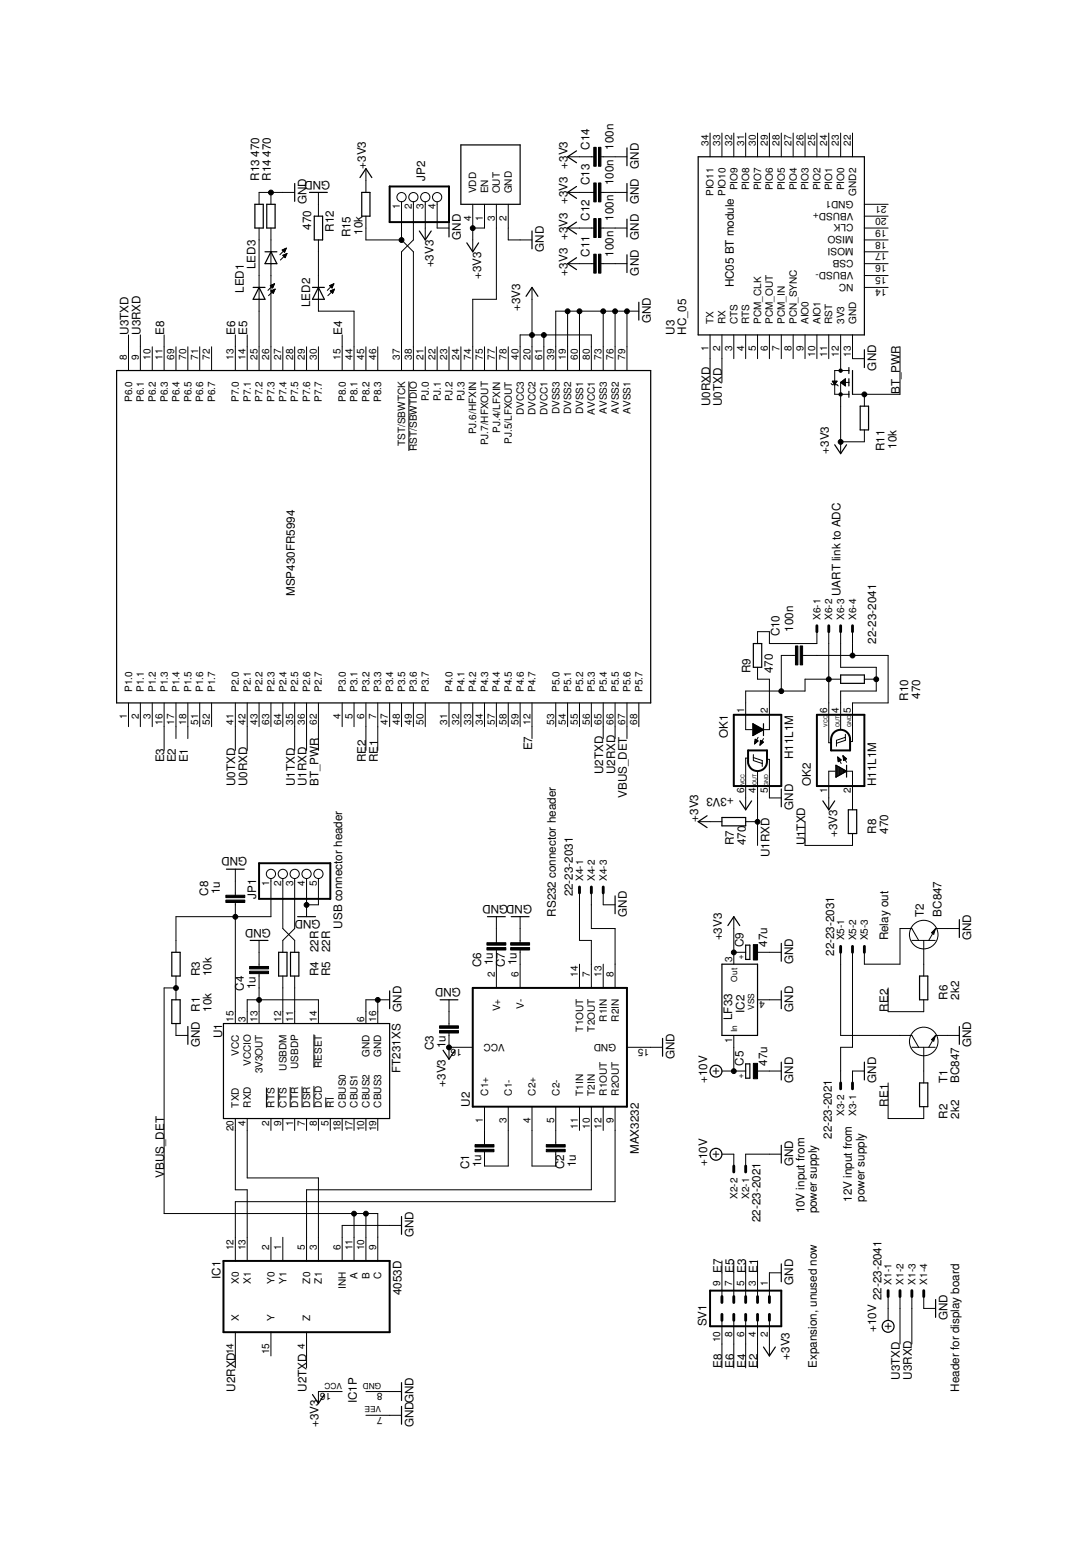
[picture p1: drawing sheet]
<svg xmlns="http://www.w3.org/2000/svg" width="210mm" height="297mm" viewBox="0 0 210 297" stroke-linecap="round" stroke-linejoin="round" font-family="sans-serif">
<defs><g id="words">
<g font-size="2.2">
<text x="109.3" y="29.9" transform="rotate(-90 109.3 29.9)">V3</text>
<text x="113.5" y="28.8" transform="rotate(-90 113.5 28.8)">C14</text>
<text x="118.1" y="28.8" transform="rotate(-90 118.1 28.8)">100n</text>
<text x="49.9" y="34.8" transform="rotate(-90 49.9 34.8)">R13</text>
<text x="49.9" y="30.2" transform="rotate(-90 49.9 30.2)">470</text>
<text x="52.2" y="34.8" transform="rotate(-90 52.2 34.8)">R14</text>
<text x="52.2" y="30.2" transform="rotate(-90 52.2 30.2)">470</text>
<text x="63.6" y="34.8" transform="rotate(-180 63.6 34.8)">GND</text>
<text x="70.5" y="32.5" transform="rotate(-90 70.5 32.5)">+3V3</text>
<text x="81.9" y="34.8" transform="rotate(-90 81.9 34.8)">JP2</text>
<text x="113.5" y="35.7" transform="rotate(-90 113.5 35.7)">C13</text>
<text x="118.1" y="35.7" transform="rotate(-90 118.1 35.7)">100n</text>
<text x="123" y="32.5" transform="rotate(-90 123 32.5)">GND</text>
<text x="59" y="39.3" transform="rotate(-90 59 39.3)">GND</text>
<text x="109.3" y="36.8" transform="rotate(-90 109.3 36.8)">V3 +3</text>
<text x="123" y="39.3" transform="rotate(-90 123 39.3)">GND</text>
<text x="60" y="44.2" transform="rotate(-90 60 44.2)">470</text>
<text x="64.3" y="44.6" transform="rotate(-90 64.3 44.6)">R12</text>
<text x="67.5" y="45.7" transform="rotate(-90 67.5 45.7)">R15</text>
<text x="69.8" y="45.2" transform="rotate(-90 69.8 45.2)">10k</text>
<text x="88.7" y="46.2" transform="rotate(-90 88.7 46.2)">GND</text>
<text x="109.3" y="43.6" transform="rotate(-90 109.3 43.6)">V3 +3</text>
<text x="113.5" y="42.5" transform="rotate(-90 113.5 42.5)">C12</text>
<text x="118.1" y="42.5" transform="rotate(-90 118.1 42.5)">100n</text>
<text x="123" y="46.2" transform="rotate(-90 123 46.2)">GND</text>
<text x="49.2" y="51.8" transform="rotate(-90 49.2 51.8)">LED3</text>
<text x="83.5" y="51.5" transform="rotate(-90 83.5 51.5)">+3V3</text>
<text x="92.6" y="53.8" transform="rotate(-90 92.6 53.8)">+3V3</text>
<text x="104.7" y="48.5" transform="rotate(-90 104.7 48.5)">GND</text>
<text x="109.3" y="53" transform="rotate(-90 109.3 53)">+3</text>
<text x="109.3" y="50.5" transform="rotate(-90 109.3 50.5)">V3 +3</text>
<text x="113.5" y="49.4" transform="rotate(-90 113.5 49.4)">C11</text>
<text x="118.1" y="49.4" transform="rotate(-90 118.1 49.4)">100n</text>
<text x="123" y="53" transform="rotate(-90 123 53)">GND</text>
<text x="46.9" y="56.4" transform="rotate(-90 46.9 56.4)">LED1</text>
<text x="59.7" y="59.1" transform="rotate(-90 59.7 59.1)">LED2</text>
<text x="100.2" y="59.9" transform="rotate(-90 100.2 59.9)">+3V3</text>
<text x="141.3" y="55.3" transform="rotate(-90 141.3 55.3)">HC05 BT module</text>
<text x="24.7" y="64.5" transform="rotate(-90 24.7 64.5)">U3TXD</text>
<text x="27" y="64.5" transform="rotate(-90 27 64.5)">U3RXD</text>
<text x="31.6" y="64.5" transform="rotate(-90 31.6 64.5)">E8</text>
<text x="45.3" y="64.5" transform="rotate(-90 45.3 64.5)">E6</text>
<text x="47.6" y="64.5" transform="rotate(-90 47.6 64.5)">E5</text>
<text x="65.9" y="64.5" transform="rotate(-90 65.9 64.5)">E4</text>
<text x="125.3" y="62.2" transform="rotate(-90 125.3 62.2)">GND</text>
<text x="129.9" y="64.5" transform="rotate(-90 129.9 64.5)">U3</text>
<text x="132.2" y="64.5" transform="rotate(-90 132.2 64.5)">HC_05</text>
<text x="168.7" y="71.3" transform="rotate(-90 168.7 71.3)">GND</text>
<text x="173.3" y="75.9" transform="rotate(-90 173.3 75.9)">BT_PWR</text>
<text x="136.7" y="78.2" transform="rotate(-90 136.7 78.2)">U0RXD</text>
<text x="139" y="78.2" transform="rotate(-90 139 78.2)">U0TXD</text>
<text x="159.6" y="87.3" transform="rotate(-90 159.6 87.3)">+3V3</text>
<text x="170.3" y="86.9" transform="rotate(-90 170.3 86.9)">R11</text>
<text x="172.6" y="86.4" transform="rotate(-90 172.6 86.4)">10k</text>
<text x="56.7" y="114.8" transform="rotate(-90 56.7 114.8)">MSP430FR5994</text>
<text x="161.9" y="114.8" transform="rotate(-90 161.9 114.8)">UART link to ADC</text>
<text x="150.1" y="122.5" transform="rotate(-90 150.1 122.5)">C10</text>
<text x="152.7" y="121.6" transform="rotate(-90 152.7 121.6)">100n</text>
<text x="168.7" y="123.9" transform="rotate(-90 168.7 123.9)">22-23-2041</text>
<text x="144.5" y="129.6" transform="rotate(-90 144.5 129.6)">R9</text>
<text x="148.9" y="129.6" transform="rotate(-90 148.9 129.6)">470</text>
<text x="174.9" y="134.9" transform="rotate(-90 174.9 134.9)">R10</text>
<text x="177.2" y="134.5" transform="rotate(-90 177.2 134.5)">470</text>
<text x="140.2" y="142.1" transform="rotate(-90 140.2 142.1)">OK1</text>
<text x="31.6" y="146.8" transform="rotate(-90 31.6 146.8)">E3</text>
<text x="33.9" y="146.8" transform="rotate(-90 33.9 146.8)">E2</text>
<text x="36.2" y="146.8" transform="rotate(-90 36.2 146.8)">E1</text>
<text x="70.5" y="146.8" transform="rotate(-90 70.5 146.8)">RE2</text>
<text x="72.7" y="146.8" transform="rotate(-90 72.7 146.8)">RE1</text>
<text x="102.5" y="144.5" transform="rotate(-90 102.5 144.5)">E7</text>
<text x="116.2" y="149" transform="rotate(-90 116.2 149)">U2TXD</text>
<text x="118.5" y="149" transform="rotate(-90 118.5 149)">U2RXD</text>
<text x="152.7" y="146.1" transform="rotate(-90 152.7 146.1)">H11L1M</text>
<text x="45.3" y="151.3" transform="rotate(-90 45.3 151.3)">U0TXD</text>
<text x="47.6" y="151.3" transform="rotate(-90 47.6 151.3)">U0RXD</text>
<text x="56.7" y="151.3" transform="rotate(-90 56.7 151.3)">U1TXD</text>
<text x="59" y="151.3" transform="rotate(-90 59 151.3)">U1RXD</text>
<text x="61.3" y="151.3" transform="rotate(-90 61.3 151.3)">BT_PWR</text>
<text x="120.7" y="153.6" transform="rotate(-90 120.7 153.6)">VBUS_DET</text>
<text x="141.3" y="153.6" transform="rotate(-180 141.3 153.6)">+3V3</text>
<text x="152.7" y="155.9" transform="rotate(-90 152.7 155.9)">GND</text>
<text x="156.2" y="151.3" transform="rotate(-90 156.2 151.3)">OK2</text>
<text x="168.7" y="151.3" transform="rotate(-90 168.7 151.3)">H11L1M</text>
<text x="134.5" y="158.2" transform="rotate(-90 134.5 158.2)">+3V3</text>
<text x="161.2" y="161.2" transform="rotate(-90 161.2 161.2)">+3V3</text>
<text x="168.7" y="160.5" transform="rotate(-90 168.7 160.5)">R8</text>
<text x="171" y="160.5" transform="rotate(-90 171 160.5)">470</text>
<text x="47.6" y="165" transform="rotate(-180 47.6 165)">GND</text>
<text x="141.3" y="162.8" transform="rotate(-90 141.3 162.8)">R7</text>
<text x="143.6" y="162.8" transform="rotate(-90 143.6 162.8)">470</text>
<text x="148.2" y="165" transform="rotate(-90 148.2 165)">U1RXD</text>
<text x="155" y="162.8" transform="rotate(-90 155 162.8)">U1TXD</text>
<text x="40.1" y="172.5" transform="rotate(-90 40.1 172.5)">C8</text>
<text x="42.4" y="172.1" transform="rotate(-90 42.4 172.1)">1u</text>
<text x="49.3" y="173" transform="rotate(-90 49.3 173)">JP1</text>
<text x="110.3" y="172.6" transform="rotate(-90 110.3 172.6)">22-23-2031</text>
<text x="52.2" y="178.8" transform="rotate(-180 52.2 178.8)">GND</text>
<text x="61.7" y="177.1" transform="rotate(-180 61.7 177.1)">GND</text>
<text x="65.9" y="178.8" transform="rotate(-90 65.9 178.8)">USB connector header</text>
<text x="102.5" y="174.2" transform="rotate(-180 102.5 174.2)">GNDGND</text>
<text x="107" y="176.5" transform="rotate(-90 107 176.5)">RS232 connector header</text>
<text x="120.7" y="176.5" transform="rotate(-90 120.7 176.5)">GND</text>
<text x="177.9" y="176.5" transform="rotate(-90 177.9 176.5)">T2</text>
<text x="181.3" y="176.5" transform="rotate(-90 181.3 176.5)">BC847</text>
<text x="61.3" y="183.3" transform="rotate(-90 61.3 183.3)">22R</text>
<text x="63.6" y="183.3" transform="rotate(-90 63.6 183.3)">22R</text>
<text x="94.9" y="185.8" transform="rotate(-90 94.9 185.8)">1u</text>
<text x="99.5" y="185.8" transform="rotate(-90 99.5 185.8)">1u</text>
<text x="139" y="181" transform="rotate(-90 139 181)">+3V3</text>
<text x="143.2" y="182.3" transform="rotate(-90 143.2 182.3)">C9</text>
<text x="147.7" y="182.3" transform="rotate(-90 147.7 182.3)">47u</text>
<text x="152.7" y="185.6" transform="rotate(-90 152.7 185.6)">GND</text>
<text x="160.6" y="184" transform="rotate(-90 160.6 184)">22-23-2031</text>
<text x="171" y="181" transform="rotate(-90 171 181)">Relay out</text>
<text x="187" y="181" transform="rotate(-90 187 181)">GND</text>
<text x="38.5" y="187.9" transform="rotate(-90 38.5 187.9)">R3</text>
<text x="40.7" y="187.9" transform="rotate(-90 40.7 187.9)">10k</text>
<text x="46.9" y="190.8" transform="rotate(-90 46.9 190.8)">C4</text>
<text x="49.2" y="190.4" transform="rotate(-90 49.2 190.4)">1u</text>
<text x="61.3" y="187.9" transform="rotate(-90 61.3 187.9)">R4</text>
<text x="63.6" y="187.9" transform="rotate(-90 63.6 187.9)">R5</text>
<text x="88.7" y="190.2" transform="rotate(-180 88.7 190.2)">GND</text>
<text x="92.6" y="186.2" transform="rotate(-90 92.6 186.2)">C6</text>
<text x="97.2" y="186.2" transform="rotate(-90 97.2 186.2)">C7</text>
<text x="38.5" y="194.8" transform="rotate(-90 38.5 194.8)">R1</text>
<text x="40.7" y="194.8" transform="rotate(-90 40.7 194.8)">10k</text>
<text x="77.3" y="194.8" transform="rotate(-90 77.3 194.8)">GND</text>
<text x="141" y="196.4" transform="rotate(-90 141 196.4)">LF33</text>
<text x="143.4" y="195" transform="rotate(-90 143.4 195)">IC2</text>
<text x="152.7" y="194.8" transform="rotate(-90 152.7 194.8)">GND</text>
<text x="171" y="194.8" transform="rotate(-90 171 194.8)">RE2</text>
<text x="182.4" y="192.5" transform="rotate(-90 182.4 192.5)">R6</text>
<text x="184.7" y="192.5" transform="rotate(-90 184.7 192.5)">2k2</text>
<text x="38.5" y="201.6" transform="rotate(-90 38.5 201.6)">GND</text>
<text x="42.8" y="199.9" transform="rotate(-90 42.8 199.9)">U1</text>
<text x="83.5" y="202.2" transform="rotate(-90 83.5 202.2)">C3</text>
<text x="85.8" y="201.8" transform="rotate(-90 85.8 201.8)">1u</text>
<text x="129.9" y="203.9" transform="rotate(-90 129.9 203.9)">GND</text>
<text x="187" y="201.6" transform="rotate(-90 187 201.6)">GND</text>
<text x="77.1" y="206.5" transform="rotate(-90 77.1 206.5)">FT231XS</text>
<text x="85.8" y="209.2" transform="rotate(-90 85.8 209.2)">+3V3</text>
<text x="136.2" y="208.5" transform="rotate(-90 136.2 208.5)">+10V</text>
<text x="143.2" y="205.2" transform="rotate(-90 143.2 205.2)">C5</text>
<text x="147.7" y="205.2" transform="rotate(-90 147.7 205.2)">47u</text>
<text x="152.7" y="208.5" transform="rotate(-90 152.7 208.5)">GND</text>
<text x="168.7" y="208.5" transform="rotate(-90 168.7 208.5)">GND</text>
<text x="182.4" y="208.5" transform="rotate(-90 182.4 208.5)">T1</text>
<text x="184.7" y="208.5" transform="rotate(-90 184.7 208.5)">BC847</text>
<text x="90.5" y="213" transform="rotate(-90 90.5 213)">U2</text>
<text x="171" y="213" transform="rotate(-90 171 213)">RE1</text>
<text x="182.4" y="215.3" transform="rotate(-90 182.4 215.3)">R2</text>
<text x="184.7" y="215.3" transform="rotate(-90 184.7 215.3)">2k2</text>
<text x="160.2" y="219.3" transform="rotate(-90 160.2 219.3)">22-23-2021</text>
<text x="31.6" y="226.8" transform="rotate(-90 31.6 226.8)">VBUS_DET</text>
<text x="90.4" y="225" transform="rotate(-90 90.4 225)">C1</text>
<text x="92.6" y="224.7" transform="rotate(-90 92.6 224.7)">1u</text>
<text x="108.6" y="225" transform="rotate(-90 108.6 225)">C2</text>
<text x="110.9" y="224.7" transform="rotate(-90 110.9 224.7)">1u</text>
<text x="123" y="222.2" transform="rotate(-90 123 222.2)">MAX3232</text>
<text x="136.2" y="224.5" transform="rotate(-90 136.2 224.5)">+10V</text>
<text x="152.7" y="224.5" transform="rotate(-90 152.7 224.5)">GND</text>
<text x="154.9" y="233.6" transform="rotate(-90 154.9 233.6)">10V input from</text>
<text x="157.3" y="233.6" transform="rotate(-90 157.3 233.6)">power supply</text>
<text x="164.1" y="231.3" transform="rotate(-90 164.1 231.3)">12V input from</text>
<text x="166.4" y="231.3" transform="rotate(-90 166.4 231.3)">power supply</text>
<text x="79.6" y="238.2" transform="rotate(-90 79.6 238.2)">GND</text>
<text x="146.5" y="235.3" transform="rotate(-90 146.5 235.3)">22-23-2021</text>
<text x="139" y="245" transform="rotate(-90 139 245)">E7</text>
<text x="141.3" y="245" transform="rotate(-90 141.3 245)">E5</text>
<text x="143.6" y="245" transform="rotate(-90 143.6 245)">E3</text>
<text x="145.9" y="245" transform="rotate(-90 145.9 245)">E1</text>
<text x="42.5" y="246.2" transform="rotate(-90 42.5 246.2)">IC1</text>
<text x="77.3" y="249.4" transform="rotate(-90 77.3 249.4)">4053D</text>
<text x="152.7" y="247.3" transform="rotate(-90 152.7 247.3)">GND</text>
<text x="169.8" y="250.3" transform="rotate(-90 169.8 250.3)">22-23-2041</text>
<text x="136.1" y="255.3" transform="rotate(-90 136.1 255.3)">SV1</text>
<text x="168.7" y="256.5" transform="rotate(-90 168.7 256.5)">+10V</text>
<text x="182.4" y="254.2" transform="rotate(-90 182.4 254.2)">GND</text>
<text x="139" y="263.3" transform="rotate(-90 139 263.3)">E8</text>
<text x="141.3" y="263.3" transform="rotate(-90 141.3 263.3)">E6</text>
<text x="143.6" y="263.3" transform="rotate(-90 143.6 263.3)">E4</text>
<text x="145.9" y="263.3" transform="rotate(-90 145.9 263.3)">E2</text>
<text x="152.1" y="261.8" transform="rotate(-90 152.1 261.8)">+3V3</text>
<text x="157.3" y="263.3" transform="rotate(-90 157.3 263.3)">Expansion, unused now</text>
<text x="45.3" y="267.9" transform="rotate(-90 45.3 267.9)">U2RXD</text>
<text x="59" y="267.9" transform="rotate(-90 59 267.9)">U2TXD</text>
<text x="173.3" y="265.6" transform="rotate(-90 173.3 265.6)">U3TXD</text>
<text x="175.6" y="265.6" transform="rotate(-90 175.6 265.6)">U3RXD</text>
<text x="184.7" y="267.9" transform="rotate(-90 184.7 267.9)">Header for display board</text>
<text x="61.3" y="274.7" transform="rotate(-90 61.3 274.7)">+3V3</text>
<text x="68.7" y="270.2" transform="rotate(-90 68.7 270.2)">IC1P</text>
<text x="79.6" y="274.7" transform="rotate(-90 79.6 274.7)">GNDGND</text>
</g>
<g font-size="1.9">
<text x="136.4" y="28.1" transform="rotate(-90 136.4 28.1)">34</text>
<text x="138.7" y="28.1" transform="rotate(-90 138.7 28.1)">33</text>
<text x="141" y="28.1" transform="rotate(-90 141 28.1)">32</text>
<text x="143.3" y="28.1" transform="rotate(-90 143.3 28.1)">31</text>
<text x="145.6" y="28.1" transform="rotate(-90 145.6 28.1)">30</text>
<text x="147.8" y="28.1" transform="rotate(-90 147.8 28.1)">29</text>
<text x="150.1" y="28.1" transform="rotate(-90 150.1 28.1)">28</text>
<text x="152.4" y="28.1" transform="rotate(-90 152.4 28.1)">27</text>
<text x="154.7" y="28.1" transform="rotate(-90 154.7 28.1)">26</text>
<text x="157" y="28.1" transform="rotate(-90 157 28.1)">25</text>
<text x="159.3" y="28.1" transform="rotate(-90 159.3 28.1)">24</text>
<text x="161.6" y="28.1" transform="rotate(-90 161.6 28.1)">23</text>
<text x="163.8" y="28.1" transform="rotate(-90 163.8 28.1)">22</text>
<text x="77" y="40.2" transform="rotate(-90 77 40.2)">1</text>
<text x="79.3" y="40.2" transform="rotate(-90 79.3 40.2)">2</text>
<text x="81.6" y="40.2" transform="rotate(-90 81.6 40.2)">3</text>
<text x="83.9" y="40.2" transform="rotate(-90 83.9 40.2)">4</text>
<text x="91.7" y="37.2" transform="rotate(-90 91.7 37.2)">VDD</text>
<text x="94" y="37.2" transform="rotate(-90 94 37.2)">EN</text>
<text x="96.3" y="37.2" transform="rotate(-90 96.3 37.2)">OUT</text>
<text x="98.6" y="37.2" transform="rotate(-90 98.6 37.2)">GND</text>
<text x="137.4" y="37.7" transform="rotate(-90 137.4 37.7)">PIO11</text>
<text x="139.7" y="37.7" transform="rotate(-90 139.7 37.7)">PIO10</text>
<text x="142" y="36.7" transform="rotate(-90 142 36.7)">PIO9</text>
<text x="144.3" y="36.7" transform="rotate(-90 144.3 36.7)">PIO8</text>
<text x="146.6" y="36.7" transform="rotate(-90 146.6 36.7)">PIO7</text>
<text x="148.9" y="36.7" transform="rotate(-90 148.9 36.7)">PIO6</text>
<text x="151.1" y="36.7" transform="rotate(-90 151.1 36.7)">PIO5</text>
<text x="153.4" y="36.7" transform="rotate(-90 153.4 36.7)">PIO4</text>
<text x="155.7" y="36.7" transform="rotate(-90 155.7 36.7)">PIO3</text>
<text x="158" y="36.7" transform="rotate(-90 158 36.7)">PIO2</text>
<text x="160.3" y="36.7" transform="rotate(-90 160.3 36.7)">PIO1</text>
<text x="162.6" y="36.7" transform="rotate(-90 162.6 36.7)">PIO0</text>
<text x="164.3" y="40.9" transform="rotate(-180 164.3 40.9)">VBUSD+</text>
<text x="164.3" y="38.6" transform="rotate(-180 164.3 38.6)">GND1</text>
<text x="164.9" y="37.6" transform="rotate(-90 164.9 37.6)">GND2</text>
<text x="170.7" y="41.9" transform="rotate(-180 170.7 41.9)">20</text>
<text x="170.7" y="39.6" transform="rotate(-180 170.7 39.6)">21</text>
<text x="90.7" y="42.5" transform="rotate(-90 90.7 42.5)">4</text>
<text x="93" y="42.5" transform="rotate(-90 93 42.5)">1</text>
<text x="95.3" y="42.5" transform="rotate(-90 95.3 42.5)">3</text>
<text x="97.6" y="42.5" transform="rotate(-90 97.6 42.5)">2</text>
<text x="164.3" y="47.8" transform="rotate(-180 164.3 47.8)">MOSI</text>
<text x="164.3" y="45.5" transform="rotate(-180 164.3 45.5)">MISO</text>
<text x="164.3" y="43.2" transform="rotate(-180 164.3 43.2)">CLK</text>
<text x="170.7" y="46.5" transform="rotate(-180 170.7 46.5)">18</text>
<text x="170.7" y="44.2" transform="rotate(-180 170.7 44.2)">19</text>
<text x="164.3" y="52.4" transform="rotate(-180 164.3 52.4)">VBUSD-</text>
<text x="164.3" y="50.1" transform="rotate(-180 164.3 50.1)">CSB</text>
<text x="170.7" y="53.4" transform="rotate(-180 170.7 53.4)">15</text>
<text x="170.7" y="51.1" transform="rotate(-180 170.7 51.1)">16</text>
<text x="170.7" y="48.8" transform="rotate(-180 170.7 48.8)">17</text>
<text x="164.3" y="54.6" transform="rotate(-180 164.3 54.6)">NC</text>
<text x="170.7" y="55.6" transform="rotate(-180 170.7 55.6)">14</text>
<text x="137.4" y="62.4" transform="rotate(-90 137.4 62.4)">TX</text>
<text x="139.7" y="62.4" transform="rotate(-90 139.7 62.4)">RX</text>
<text x="142" y="62.4" transform="rotate(-90 142 62.4)">CTS</text>
<text x="144.3" y="62.4" transform="rotate(-90 144.3 62.4)">RTS</text>
<text x="146.6" y="62.4" transform="rotate(-90 146.6 62.4)">PCM_CLK</text>
<text x="148.9" y="62.4" transform="rotate(-90 148.9 62.4)">PCM_OUT</text>
<text x="151.1" y="62.4" transform="rotate(-90 151.1 62.4)">PCM_IN</text>
<text x="153.4" y="62.4" transform="rotate(-90 153.4 62.4)">PCN_SYNC</text>
<text x="155.7" y="62.4" transform="rotate(-90 155.7 62.4)">AIO0</text>
<text x="158" y="62.4" transform="rotate(-90 158 62.4)">AIO1</text>
<text x="160.3" y="62.4" transform="rotate(-90 160.3 62.4)">RST</text>
<text x="162.6" y="62.4" transform="rotate(-90 162.6 62.4)">3V3</text>
<text x="164.9" y="62.4" transform="rotate(-90 164.9 62.4)">GND</text>
<text x="24.4" y="69.2" transform="rotate(-90 24.4 69.2)">8</text>
<text x="26.7" y="69.2" transform="rotate(-90 26.7 69.2)">9</text>
<text x="29" y="69.2" transform="rotate(-90 29 69.2)">10</text>
<text x="31.3" y="69.2" transform="rotate(-90 31.3 69.2)">11</text>
<text x="33.6" y="69.2" transform="rotate(-90 33.6 69.2)">69</text>
<text x="35.9" y="69.2" transform="rotate(-90 35.9 69.2)">70</text>
<text x="38.1" y="69.2" transform="rotate(-90 38.1 69.2)">71</text>
<text x="40.4" y="69.2" transform="rotate(-90 40.4 69.2)">72</text>
<text x="45" y="69.2" transform="rotate(-90 45 69.2)">13</text>
<text x="47.3" y="69.2" transform="rotate(-90 47.3 69.2)">14</text>
<text x="49.6" y="69.2" transform="rotate(-90 49.6 69.2)">25</text>
<text x="51.9" y="69.2" transform="rotate(-90 51.9 69.2)">26</text>
<text x="54.1" y="69.2" transform="rotate(-90 54.1 69.2)">27</text>
<text x="56.4" y="69.2" transform="rotate(-90 56.4 69.2)">28</text>
<text x="58.7" y="69.2" transform="rotate(-90 58.7 69.2)">29</text>
<text x="61" y="69.2" transform="rotate(-90 61 69.2)">30</text>
<text x="65.6" y="69.2" transform="rotate(-90 65.6 69.2)">15</text>
<text x="67.9" y="69.2" transform="rotate(-90 67.9 69.2)">44</text>
<text x="70.1" y="69.2" transform="rotate(-90 70.1 69.2)">45</text>
<text x="72.4" y="69.2" transform="rotate(-90 72.4 69.2)">46</text>
<text x="77" y="69.2" transform="rotate(-90 77 69.2)">37</text>
<text x="79.3" y="69.2" transform="rotate(-90 79.3 69.2)">38</text>
<text x="81.6" y="69.2" transform="rotate(-90 81.6 69.2)">21</text>
<text x="83.9" y="69.2" transform="rotate(-90 83.9 69.2)">22</text>
<text x="86.1" y="69.2" transform="rotate(-90 86.1 69.2)">23</text>
<text x="88.4" y="69.2" transform="rotate(-90 88.4 69.2)">24</text>
<text x="90.7" y="69.2" transform="rotate(-90 90.7 69.2)">74</text>
<text x="93" y="69.2" transform="rotate(-90 93 69.2)">75</text>
<text x="95.3" y="69.2" transform="rotate(-90 95.3 69.2)">77</text>
<text x="97.6" y="69.2" transform="rotate(-90 97.6 69.2)">78</text>
<text x="99.8" y="69.2" transform="rotate(-90 99.8 69.2)">40</text>
<text x="102.1" y="69.2" transform="rotate(-90 102.1 69.2)">20</text>
<text x="104.4" y="69.2" transform="rotate(-90 104.4 69.2)">61</text>
<text x="106.7" y="69.2" transform="rotate(-90 106.7 69.2)">39</text>
<text x="109" y="69.2" transform="rotate(-90 109 69.2)">19</text>
<text x="111.3" y="69.2" transform="rotate(-90 111.3 69.2)">60</text>
<text x="113.6" y="69.2" transform="rotate(-90 113.6 69.2)">80</text>
<text x="115.8" y="69.2" transform="rotate(-90 115.8 69.2)">73</text>
<text x="118.1" y="69.2" transform="rotate(-90 118.1 69.2)">76</text>
<text x="120.4" y="69.2" transform="rotate(-90 120.4 69.2)">79</text>
<text x="136.4" y="67.7" transform="rotate(-90 136.4 67.7)">1</text>
<text x="138.7" y="67.7" transform="rotate(-90 138.7 67.7)">2</text>
<text x="141" y="67.7" transform="rotate(-90 141 67.7)">3</text>
<text x="143.3" y="67.7" transform="rotate(-90 143.3 67.7)">4</text>
<text x="145.6" y="67.7" transform="rotate(-90 145.6 67.7)">5</text>
<text x="147.8" y="67.7" transform="rotate(-90 147.8 67.7)">6</text>
<text x="150.1" y="67.7" transform="rotate(-90 150.1 67.7)">7</text>
<text x="152.4" y="67.7" transform="rotate(-90 152.4 67.7)">8</text>
<text x="154.7" y="67.7" transform="rotate(-90 154.7 67.7)">9</text>
<text x="157" y="68.7" transform="rotate(-90 157 68.7)">10</text>
<text x="159.3" y="68.7" transform="rotate(-90 159.3 68.7)">11</text>
<text x="161.6" y="68.7" transform="rotate(-90 161.6 68.7)">12</text>
<text x="163.8" y="68.7" transform="rotate(-90 163.8 68.7)">13</text>
<text x="25.4" y="77.4" transform="rotate(-90 25.4 77.4)">P6.0</text>
<text x="27.7" y="77.4" transform="rotate(-90 27.7 77.4)">P6.1</text>
<text x="30" y="77.4" transform="rotate(-90 30 77.4)">P6.2</text>
<text x="32.3" y="77.4" transform="rotate(-90 32.3 77.4)">P6.3</text>
<text x="34.6" y="77.4" transform="rotate(-90 34.6 77.4)">P6.4</text>
<text x="36.9" y="77.4" transform="rotate(-90 36.9 77.4)">P6.5</text>
<text x="39.2" y="77.4" transform="rotate(-90 39.2 77.4)">P6.6</text>
<text x="41.4" y="77.4" transform="rotate(-90 41.4 77.4)">P6.7</text>
<text x="46" y="77.4" transform="rotate(-90 46 77.4)">P7.0</text>
<text x="48.3" y="77.4" transform="rotate(-90 48.3 77.4)">P7.1</text>
<text x="50.6" y="77.4" transform="rotate(-90 50.6 77.4)">P7.2</text>
<text x="52.9" y="77.4" transform="rotate(-90 52.9 77.4)">P7.3</text>
<text x="55.1" y="77.4" transform="rotate(-90 55.1 77.4)">P7.4</text>
<text x="57.4" y="77.4" transform="rotate(-90 57.4 77.4)">P7.5</text>
<text x="59.7" y="77.4" transform="rotate(-90 59.7 77.4)">P7.6</text>
<text x="62" y="77.4" transform="rotate(-90 62 77.4)">P7.7</text>
<text x="66.6" y="77.4" transform="rotate(-90 66.6 77.4)">P8.0</text>
<text x="68.9" y="77.4" transform="rotate(-90 68.9 77.4)">P8.1</text>
<text x="71.1" y="77.4" transform="rotate(-90 71.1 77.4)">P8.2</text>
<text x="73.4" y="77.4" transform="rotate(-90 73.4 77.4)">P8.3</text>
<text x="82.6" y="77.3" transform="rotate(-90 82.6 77.3)">PJ.0</text>
<text x="84.9" y="77.3" transform="rotate(-90 84.9 77.3)">PJ.1</text>
<text x="87.1" y="77.3" transform="rotate(-90 87.1 77.3)">PJ.2</text>
<text x="89.4" y="77.3" transform="rotate(-90 89.4 77.3)">PJ.3</text>
<text x="91.7" y="83.6" transform="rotate(-90 91.7 83.6)">PJ.6/HFXIN</text>
<text x="96.3" y="83.3" transform="rotate(-90 96.3 83.3)">PJ.4/LFXIN</text>
<text x="100.9" y="79.9" transform="rotate(-90 100.9 79.9)">DVCC3</text>
<text x="103.1" y="79.9" transform="rotate(-90 103.1 79.9)">DVCC2</text>
<text x="105.4" y="79.9" transform="rotate(-90 105.4 79.9)">DVCC1</text>
<text x="107.7" y="79.7" transform="rotate(-90 107.7 79.7)">DVSS3</text>
<text x="110" y="79.7" transform="rotate(-90 110 79.7)">DVSS2</text>
<text x="112.3" y="79.7" transform="rotate(-90 112.3 79.7)">DVSS1</text>
<text x="114.6" y="79.8" transform="rotate(-90 114.6 79.8)">AVCC1</text>
<text x="116.9" y="79.6" transform="rotate(-90 116.9 79.6)">AVSS3</text>
<text x="119.1" y="79.6" transform="rotate(-90 119.1 79.6)">AVSS2</text>
<text x="121.4" y="79.6" transform="rotate(-90 121.4 79.6)">AVSS1</text>
<text x="78" y="85.8" transform="rotate(-90 78 85.8)">TST/SBWTCK</text>
<text x="80.3" y="86.8" transform="rotate(-90 80.3 86.8)">RST/SBWTDIO</text>
<text x="94" y="85.7" transform="rotate(-90 94 85.7)">PJ.7/HFXOUT</text>
<text x="98.6" y="85.4" transform="rotate(-90 98.6 85.4)">PJ.5/LFXOUT</text>
<text x="158" y="119.3" transform="rotate(-90 158 119.3)">X6-1</text>
<text x="160.3" y="119.3" transform="rotate(-90 160.3 119.3)">X6-2</text>
<text x="162.6" y="119.3" transform="rotate(-90 162.6 119.3)">X6-3</text>
<text x="164.9" y="119.3" transform="rotate(-90 164.9 119.3)">X6-4</text>
<text x="25.4" y="133.2" transform="rotate(-90 25.4 133.2)">P1.0</text>
<text x="27.7" y="133.2" transform="rotate(-90 27.7 133.2)">P1.1</text>
<text x="30" y="133.2" transform="rotate(-90 30 133.2)">P1.2</text>
<text x="32.3" y="133.2" transform="rotate(-90 32.3 133.2)">P1.3</text>
<text x="34.6" y="133.2" transform="rotate(-90 34.6 133.2)">P1.4</text>
<text x="36.9" y="133.2" transform="rotate(-90 36.9 133.2)">P1.5</text>
<text x="39.1" y="133.2" transform="rotate(-90 39.1 133.2)">P1.6</text>
<text x="41.4" y="133.2" transform="rotate(-90 41.4 133.2)">P1.7</text>
<text x="46" y="133.2" transform="rotate(-90 46 133.2)">P2.0</text>
<text x="48.3" y="133.2" transform="rotate(-90 48.3 133.2)">P2.1</text>
<text x="50.6" y="133.2" transform="rotate(-90 50.6 133.2)">P2.2</text>
<text x="52.9" y="133.2" transform="rotate(-90 52.9 133.2)">P2.3</text>
<text x="55.1" y="133.2" transform="rotate(-90 55.1 133.2)">P2.4</text>
<text x="57.4" y="133.2" transform="rotate(-90 57.4 133.2)">P2.5</text>
<text x="59.7" y="133.2" transform="rotate(-90 59.7 133.2)">P2.6</text>
<text x="62" y="133.2" transform="rotate(-90 62 133.2)">P2.7</text>
<text x="66.6" y="133.2" transform="rotate(-90 66.6 133.2)">P3.0</text>
<text x="68.9" y="133.2" transform="rotate(-90 68.9 133.2)">P3.1</text>
<text x="71.1" y="133.2" transform="rotate(-90 71.1 133.2)">P3.2</text>
<text x="73.4" y="133.2" transform="rotate(-90 73.4 133.2)">P3.3</text>
<text x="75.7" y="133.2" transform="rotate(-90 75.7 133.2)">P3.4</text>
<text x="78" y="133.2" transform="rotate(-90 78 133.2)">P3.5</text>
<text x="80.3" y="133.2" transform="rotate(-90 80.3 133.2)">P3.6</text>
<text x="82.6" y="133.2" transform="rotate(-90 82.6 133.2)">P3.7</text>
<text x="87.1" y="133.2" transform="rotate(-90 87.1 133.2)">P4.0</text>
<text x="89.4" y="133.2" transform="rotate(-90 89.4 133.2)">P4.1</text>
<text x="91.7" y="133.2" transform="rotate(-90 91.7 133.2)">P4.2</text>
<text x="94" y="133.2" transform="rotate(-90 94 133.2)">P4.3</text>
<text x="96.3" y="133.2" transform="rotate(-90 96.3 133.2)">P4.4</text>
<text x="98.6" y="133.2" transform="rotate(-90 98.6 133.2)">P4.5</text>
<text x="100.9" y="133.2" transform="rotate(-90 100.9 133.2)">P4.6</text>
<text x="103.1" y="133.2" transform="rotate(-90 103.1 133.2)">P4.7</text>
<text x="107.7" y="133.2" transform="rotate(-90 107.7 133.2)">P5.0</text>
<text x="110" y="133.2" transform="rotate(-90 110 133.2)">P5.1</text>
<text x="112.3" y="133.2" transform="rotate(-90 112.3 133.2)">P5.2</text>
<text x="114.6" y="133.2" transform="rotate(-90 114.6 133.2)">P5.3</text>
<text x="116.9" y="133.2" transform="rotate(-90 116.9 133.2)">P5.4</text>
<text x="119.1" y="133.2" transform="rotate(-90 119.1 133.2)">P5.5</text>
<text x="121.4" y="133.2" transform="rotate(-90 121.4 133.2)">P5.6</text>
<text x="123.7" y="133.2" transform="rotate(-90 123.7 133.2)">P5.7</text>
<text x="143.3" y="137.3" transform="rotate(-90 143.3 137.3)">1</text>
<text x="147.8" y="137.3" transform="rotate(-90 147.8 137.3)">2</text>
<text x="159.3" y="137.3" transform="rotate(-90 159.3 137.3)">6</text>
<text x="161.6" y="137.3" transform="rotate(-90 161.6 137.3)">4</text>
<text x="163.8" y="137.3" transform="rotate(-90 163.8 137.3)">5</text>
<text x="24.4" y="138.5" transform="rotate(-90 24.4 138.5)">1</text>
<text x="26.7" y="138.5" transform="rotate(-90 26.7 138.5)">2</text>
<text x="29" y="138.5" transform="rotate(-90 29 138.5)">3</text>
<text x="31.3" y="139.6" transform="rotate(-90 31.3 139.6)">16</text>
<text x="33.6" y="139.6" transform="rotate(-90 33.6 139.6)">17</text>
<text x="35.9" y="139.6" transform="rotate(-90 35.9 139.6)">18</text>
<text x="38.1" y="139.6" transform="rotate(-90 38.1 139.6)">51</text>
<text x="40.4" y="139.6" transform="rotate(-90 40.4 139.6)">52</text>
<text x="45" y="139.6" transform="rotate(-90 45 139.6)">41</text>
<text x="47.3" y="139.6" transform="rotate(-90 47.3 139.6)">42</text>
<text x="49.6" y="139.6" transform="rotate(-90 49.6 139.6)">43</text>
<text x="51.9" y="139.6" transform="rotate(-90 51.9 139.6)">63</text>
<text x="54.1" y="139.6" transform="rotate(-90 54.1 139.6)">64</text>
<text x="56.4" y="139.6" transform="rotate(-90 56.4 139.6)">35</text>
<text x="58.7" y="139.6" transform="rotate(-90 58.7 139.6)">36</text>
<text x="61" y="139.6" transform="rotate(-90 61 139.6)">62</text>
<text x="65.6" y="138.5" transform="rotate(-90 65.6 138.5)">4</text>
<text x="67.9" y="138.5" transform="rotate(-90 67.9 138.5)">5</text>
<text x="70.1" y="138.5" transform="rotate(-90 70.1 138.5)">6</text>
<text x="72.4" y="138.5" transform="rotate(-90 72.4 138.5)">7</text>
<text x="74.7" y="139.6" transform="rotate(-90 74.7 139.6)">47</text>
<text x="77" y="139.6" transform="rotate(-90 77 139.6)">48</text>
<text x="79.3" y="139.6" transform="rotate(-90 79.3 139.6)">49</text>
<text x="81.6" y="139.6" transform="rotate(-90 81.6 139.6)">50</text>
<text x="86.1" y="139.6" transform="rotate(-90 86.1 139.6)">31</text>
<text x="88.4" y="139.6" transform="rotate(-90 88.4 139.6)">32</text>
<text x="90.7" y="139.6" transform="rotate(-90 90.7 139.6)">33</text>
<text x="93" y="139.6" transform="rotate(-90 93 139.6)">34</text>
<text x="95.3" y="139.6" transform="rotate(-90 95.3 139.6)">57</text>
<text x="97.6" y="139.6" transform="rotate(-90 97.6 139.6)">58</text>
<text x="99.8" y="139.6" transform="rotate(-90 99.8 139.6)">59</text>
<text x="102.1" y="139.6" transform="rotate(-90 102.1 139.6)">12</text>
<text x="106.7" y="139.6" transform="rotate(-90 106.7 139.6)">53</text>
<text x="109" y="139.6" transform="rotate(-90 109 139.6)">54</text>
<text x="111.3" y="139.6" transform="rotate(-90 111.3 139.6)">55</text>
<text x="113.6" y="139.6" transform="rotate(-90 113.6 139.6)">56</text>
<text x="115.8" y="139.6" transform="rotate(-90 115.8 139.6)">65</text>
<text x="118.1" y="139.6" transform="rotate(-90 118.1 139.6)">66</text>
<text x="120.4" y="139.6" transform="rotate(-90 120.4 139.6)">67</text>
<text x="122.7" y="139.6" transform="rotate(-90 122.7 139.6)">68</text>
<text x="143.3" y="152.7" transform="rotate(-90 143.3 152.7)">6</text>
<text x="145.6" y="152.7" transform="rotate(-90 145.6 152.7)">4</text>
<text x="147.8" y="152.7" transform="rotate(-90 147.8 152.7)">5</text>
<text x="159.3" y="152.7" transform="rotate(-90 159.3 152.7)">1</text>
<text x="163.8" y="152.7" transform="rotate(-90 163.8 152.7)">2</text>
<text x="51.9" y="170.5" transform="rotate(-90 51.9 170.5)">1</text>
<text x="54.1" y="170.5" transform="rotate(-90 54.1 170.5)">2</text>
<text x="56.4" y="170.5" transform="rotate(-90 56.4 170.5)">3</text>
<text x="58.7" y="170.5" transform="rotate(-90 58.7 170.5)">4</text>
<text x="61" y="170.5" transform="rotate(-90 61 170.5)">5</text>
<text x="112.3" y="169.6" transform="rotate(-90 112.3 169.6)">X4-1</text>
<text x="114.6" y="169.6" transform="rotate(-90 114.6 169.6)">X4-2</text>
<text x="116.9" y="169.6" transform="rotate(-90 116.9 169.6)">X4-3</text>
<text x="141" y="185.3" transform="rotate(-90 141 185.3)">3</text>
<text x="162.6" y="181" transform="rotate(-90 162.6 181)">X5-1</text>
<text x="164.9" y="181" transform="rotate(-90 164.9 181)">X5-2</text>
<text x="167.1" y="181" transform="rotate(-90 167.1 181)">X5-3</text>
<text x="95.3" y="188.1" transform="rotate(-90 95.3 188.1)">2</text>
<text x="99.8" y="188.1" transform="rotate(-90 99.8 188.1)">6</text>
<text x="111.3" y="188.1" transform="rotate(-90 111.3 188.1)">14</text>
<text x="113.6" y="188.1" transform="rotate(-90 113.6 188.1)">7</text>
<text x="115.8" y="188.1" transform="rotate(-90 115.8 188.1)">13</text>
<text x="118.1" y="188.1" transform="rotate(-90 118.1 188.1)">8</text>
<text x="45" y="196.7" transform="rotate(-90 45 196.7)">15</text>
<text x="47.3" y="196.7" transform="rotate(-90 47.3 196.7)">3</text>
<text x="49.6" y="196.7" transform="rotate(-90 49.6 196.7)">13</text>
<text x="54.1" y="196.7" transform="rotate(-90 54.1 196.7)">12</text>
<text x="56.4" y="196.7" transform="rotate(-90 56.4 196.7)">11</text>
<text x="61" y="196.7" transform="rotate(-90 61 196.7)">14</text>
<text x="70.1" y="196.7" transform="rotate(-90 70.1 196.7)">6</text>
<text x="72.4" y="196.7" transform="rotate(-90 72.4 196.7)">16</text>
<text x="96.3" y="194.7" transform="rotate(-90 96.3 194.7)">V+</text>
<text x="100.9" y="194.2" transform="rotate(-90 100.9 194.2)">V-</text>
<text x="116.9" y="196.7" transform="rotate(-90 116.9 196.7)">R1IN</text>
<text x="119.1" y="196.7" transform="rotate(-90 119.1 196.7)">R2IN</text>
<text x="147.3" y="192.8" transform="rotate(-180 147.3 192.8)">4</text>
<text x="46" y="203.2" transform="rotate(-90 46 203.2)">VCC</text>
<text x="71.1" y="203.4" transform="rotate(-90 71.1 203.4)">GND</text>
<text x="73.4" y="203.4" transform="rotate(-90 73.4 203.4)">GND</text>
<text x="88.9" y="201.9" transform="rotate(-180 88.9 201.9)">16</text>
<text x="97.2" y="200.9" transform="rotate(-180 97.2 200.9)">VCC</text>
<text x="112.3" y="198.6" transform="rotate(-90 112.3 198.6)">T1OUT</text>
<text x="114.6" y="198.6" transform="rotate(-90 114.6 198.6)">T2OUT</text>
<text x="118.6" y="200.9" transform="rotate(-180 118.6 200.9)">GND</text>
<text x="125" y="201.9" transform="rotate(-180 125 201.9)">15</text>
<text x="141" y="200.7" transform="rotate(-90 141 200.7)">1</text>
<text x="48.3" y="205.2" transform="rotate(-90 48.3 205.2)">VCCIO</text>
<text x="50.6" y="206.6" transform="rotate(-90 50.6 206.6)">3V3OUT</text>
<text x="55.1" y="206.1" transform="rotate(-90 55.1 206.1)">USBDM</text>
<text x="57.4" y="205.8" transform="rotate(-90 57.4 205.8)">USBDP</text>
<text x="62" y="205.6" transform="rotate(-90 62 205.6)">RESET</text>
<text x="46" y="213.2" transform="rotate(-90 46 213.2)">TXD</text>
<text x="48.3" y="213.2" transform="rotate(-90 48.3 213.2)">RXD</text>
<text x="52.9" y="213.2" transform="rotate(-90 52.9 213.2)">RTS</text>
<text x="55.1" y="213.2" transform="rotate(-90 55.1 213.2)">CTS</text>
<text x="57.4" y="213.2" transform="rotate(-90 57.4 213.2)">DTR</text>
<text x="59.7" y="213.2" transform="rotate(-90 59.7 213.2)">DSR</text>
<text x="62" y="213.2" transform="rotate(-90 62 213.2)">DCD</text>
<text x="64.3" y="213.2" transform="rotate(-90 64.3 213.2)">RI</text>
<text x="66.6" y="213.2" transform="rotate(-90 66.6 213.2)">CBUS0</text>
<text x="68.9" y="213.2" transform="rotate(-90 68.9 213.2)">CBUS1</text>
<text x="71.1" y="213.2" transform="rotate(-90 71.1 213.2)">CBUS2</text>
<text x="73.4" y="213.2" transform="rotate(-90 73.4 213.2)">CBUS3</text>
<text x="94" y="210.9" transform="rotate(-90 94 210.9)">C1+</text>
<text x="98.6" y="210.9" transform="rotate(-90 98.6 210.9)">C1-</text>
<text x="103.1" y="210.9" transform="rotate(-90 103.1 210.9)">C2+</text>
<text x="107.7" y="210.9" transform="rotate(-90 107.7 210.9)">C2-</text>
<text x="112.3" y="210.9" transform="rotate(-90 112.3 210.9)">T1IN</text>
<text x="114.6" y="210.9" transform="rotate(-90 114.6 210.9)">T2IN</text>
<text x="116.9" y="210.9" transform="rotate(-90 116.9 210.9)">R1OUT</text>
<text x="119.1" y="210.9" transform="rotate(-90 119.1 210.9)">R2OUT</text>
<text x="162.6" y="214.8" transform="rotate(-90 162.6 214.8)">X3-2</text>
<text x="164.9" y="214.8" transform="rotate(-90 164.9 214.8)">X3-1</text>
<text x="45" y="217.8" transform="rotate(-90 45 217.8)">20</text>
<text x="47.3" y="216.7" transform="rotate(-90 47.3 216.7)">4</text>
<text x="51.9" y="216.7" transform="rotate(-90 51.9 216.7)">2</text>
<text x="54.1" y="216.7" transform="rotate(-90 54.1 216.7)">9</text>
<text x="56.4" y="216.7" transform="rotate(-90 56.4 216.7)">1</text>
<text x="58.7" y="216.7" transform="rotate(-90 58.7 216.7)">7</text>
<text x="61" y="216.7" transform="rotate(-90 61 216.7)">8</text>
<text x="63.3" y="216.7" transform="rotate(-90 63.3 216.7)">5</text>
<text x="65.6" y="217.8" transform="rotate(-90 65.6 217.8)">18</text>
<text x="67.9" y="217.8" transform="rotate(-90 67.9 217.8)">17</text>
<text x="70.1" y="217.8" transform="rotate(-90 70.1 217.8)">10</text>
<text x="72.4" y="217.8" transform="rotate(-90 72.4 217.8)">19</text>
<text x="93" y="216.2" transform="rotate(-90 93 216.2)">1</text>
<text x="97.6" y="216.2" transform="rotate(-90 97.6 216.2)">3</text>
<text x="102.1" y="216.2" transform="rotate(-90 102.1 216.2)">4</text>
<text x="106.7" y="216.2" transform="rotate(-90 106.7 216.2)">5</text>
<text x="111.3" y="217.3" transform="rotate(-90 111.3 217.3)">11</text>
<text x="113.6" y="217.3" transform="rotate(-90 113.6 217.3)">10</text>
<text x="115.8" y="217.3" transform="rotate(-90 115.8 217.3)">12</text>
<text x="118.1" y="216.2" transform="rotate(-90 118.1 216.2)">9</text>
<text x="142" y="230.8" transform="rotate(-90 142 230.8)">X2-2</text>
<text x="144.3" y="230.8" transform="rotate(-90 144.3 230.8)">X2-1</text>
<text x="45" y="240.6" transform="rotate(-90 45 240.6)">12</text>
<text x="47.3" y="240.6" transform="rotate(-90 47.3 240.6)">13</text>
<text x="51.9" y="240.6" transform="rotate(-90 51.9 240.6)">2</text>
<text x="54.1" y="240.6" transform="rotate(-90 54.1 240.6)">1</text>
<text x="58.7" y="240.6" transform="rotate(-90 58.7 240.6)">5</text>
<text x="61" y="240.6" transform="rotate(-90 61 240.6)">3</text>
<text x="65.6" y="240.6" transform="rotate(-90 65.6 240.6)">6</text>
<text x="67.9" y="240.6" transform="rotate(-90 67.9 240.6)">11</text>
<text x="70.1" y="240.6" transform="rotate(-90 70.1 240.6)">10</text>
<text x="72.4" y="240.6" transform="rotate(-90 72.4 240.6)">9</text>
<text x="46" y="247.2" transform="rotate(-90 46 247.2)">X0</text>
<text x="48.3" y="247.2" transform="rotate(-90 48.3 247.2)">X1</text>
<text x="52.9" y="247.2" transform="rotate(-90 52.9 247.2)">Y0</text>
<text x="55.1" y="247.2" transform="rotate(-90 55.1 247.2)">Y1</text>
<text x="59.7" y="247.1" transform="rotate(-90 59.7 247.1)">Z0</text>
<text x="62" y="247.1" transform="rotate(-90 62 247.1)">Z1</text>
<text x="66.6" y="248.2" transform="rotate(-90 66.6 248.2)">INH</text>
<text x="68.9" y="246.1" transform="rotate(-90 68.9 246.1)">A</text>
<text x="71.1" y="246.1" transform="rotate(-90 71.1 246.1)">B</text>
<text x="73.4" y="246.2" transform="rotate(-90 73.4 246.2)">C</text>
<text x="138.7" y="247.5" transform="rotate(-90 138.7 247.5)">9</text>
<text x="141" y="247.5" transform="rotate(-90 141 247.5)">7</text>
<text x="143.3" y="247.5" transform="rotate(-90 143.3 247.5)">5</text>
<text x="145.6" y="247.5" transform="rotate(-90 145.6 247.5)">3</text>
<text x="147.8" y="247.5" transform="rotate(-90 147.8 247.5)">1</text>
<text x="171.7" y="247.3" transform="rotate(-90 171.7 247.3)">X1-1</text>
<text x="174" y="247.3" transform="rotate(-90 174 247.3)">X1-2</text>
<text x="176.3" y="247.3" transform="rotate(-90 176.3 247.3)">X1-3</text>
<text x="178.6" y="247.3" transform="rotate(-90 178.6 247.3)">X1-4</text>
<text x="46" y="254.4" transform="rotate(-90 46 254.4)">X</text>
<text x="52.9" y="254.4" transform="rotate(-90 52.9 254.4)">Y</text>
<text x="59.7" y="254.4" transform="rotate(-90 59.7 254.4)">Z</text>
<text x="141" y="257.4" transform="rotate(-90 141 257.4)">8</text>
<text x="143.3" y="257.4" transform="rotate(-90 143.3 257.4)">6</text>
<text x="145.6" y="257.4" transform="rotate(-90 145.6 257.4)">4</text>
<text x="147.8" y="257.4" transform="rotate(-90 147.8 257.4)">2</text>
<text x="45" y="260.7" transform="rotate(-90 45 260.7)">14</text>
<text x="51.9" y="260.7" transform="rotate(-90 51.9 260.7)">15</text>
<text x="58.7" y="259.6" transform="rotate(-90 58.7 259.6)">4</text>
<text x="138.7" y="258.4" transform="rotate(-90 138.7 258.4)">10</text>
<text x="63.8" y="268.2" transform="rotate(-180 63.8 268.2)">16</text>
<text x="73.6" y="268.2" transform="rotate(-180 73.6 268.2)">8</text>
<text x="73.6" y="272.8" transform="rotate(-180 73.6 272.8)">7</text>
</g>
<g font-size="1.6">
<text x="143.2" y="183.8" transform="rotate(-180 143.2 183.8)">+</text>
<text x="141.9" y="189" transform="rotate(-90 141.9 189)">Out</text>
<text x="145.3" y="194.4" transform="rotate(-90 145.3 194.4)">VSS</text>
<text x="141.9" y="198.6" transform="rotate(-90 141.9 198.6)">In</text>
<text x="143.2" y="206.7" transform="rotate(-180 143.2 206.7)">+</text>
<text x="65.9" y="266.2" transform="rotate(-180 65.9 266.2)">VCC</text>
<text x="73.4" y="266.2" transform="rotate(-180 73.4 266.2)">GND</text>
<text x="73.4" y="270.7" transform="rotate(-180 73.4 270.7)">VEE</text>
</g>
<g font-size="1">
<text x="159.4" y="139.9" transform="rotate(-90 159.4 139.9)">VCC</text>
<text x="161.7" y="139.9" transform="rotate(-90 161.7 139.9)">OUT</text>
<text x="163.9" y="139.9" transform="rotate(-90 163.9 139.9)">GND</text>
<text x="143.4" y="151.2" transform="rotate(-90 143.4 151.2)">VCC</text>
<text x="145.7" y="151.2" transform="rotate(-90 145.7 151.2)">OUT</text>
<text x="147.9" y="151.3" transform="rotate(-90 147.9 151.3)">GND</text>
</g>
</g></defs>
<g fill="none" stroke="#000" stroke-width=".19">
<path d="M52.2 37v2.3M56.7 37h-6.8v2.3M61.3 37v4.6M70.5 32.5v4.5M77.3 38.8v7.4M79.6 38.8v7.4l-2.3 2.3v22.8M81.9 38.8v7.4M84.2 38.8v5.1h2.3M91 39.3v9.2M93.3 39.3v4.6h-2.3M95.6 39.3v18.3h-4.6v13.7M97.9 39.3v6.9h4.5"/>
<path d="M109.3 37h5M109.3 30.2h5M115.7 37h5M115.7 30.2h5M136.7 25.6v4.6M139 25.6v4.6M141.3 25.6v4.6M143.6 25.6v4.6M145.9 25.6v4.6M148.2 25.6v4.6M150.5 25.6v4.6M152.7 25.6v4.6"/>
<path d="M155 25.6v4.6M157.3 25.6v4.6M159.6 25.6v4.6M161.9 25.6v4.6M164.2 25.6v4.6M166.5 39.3h4.5M49.9 43.9v27.4M52.1 55h.1M52.2 43.9v27.4M52.2 54.9v.2M52.2 56h.1M52.3 54.9v.3"/>
<path d="M52.3 55.9v.3M52.4 54.8v.6M52.4 55.9v.4M52.5 54.8v.6M52.5 55.9v.5M52.6 54.7v.5M52.6 55.8v.7M52.7 54.7v.2M52.7 55.8v.4M52.9 54.6l-1.3 1.3M52.9 55.7v.3M52.9 54.6l-.4 .8"/>
<path d="M52.9 54.6l-.9 .4 .5 .4M52.9 54.7h.1M53 55.7h.1M53 55.7l-1.3 1.2M53 55.7l-.4 .8M53 55.7l-.8 .3 .4 .5M54.3 48.1l.8-.3-.3 .8zM54.4 48.1v.1M54.5 49.1l.8-.3-.4 .8zM54.5 48v.3M54.5 49.1v.1M54.7 48v.4"/>
<path d="M54.7 49.1v.2M54.8 48v.5M54.8 49v.4M54.8 47.9v.6M54.8 49v.6M54.9 47.9v.3M54.9 48.9v.6M55.1 47.8v.2M55.1 48.9v.4M55.1 47.8l-1.2 1.2M55.2 48.9v.1M55.3 48.8l-1.3 1.3"/>
<path d="M61.3 46.2v13.7h6.9v11.4M63.5 55l.4 .4M63.5 55h.1M63.6 56l.8-.3-.3 .8zM63.6 54.9v.2M63.7 54.9v.3M63.7 56v.1M63.8 54.8v.5M63.8 55.9v.3M63.9 54.8v.6M63.9 55.9v.4M64 54.8v.5"/>
<path d="M64 55.8v.6M64.1 54.7v.3M64.1 55.8v.5M64.2 54.7v.1M64.2 55.7v.4M64.3 54.6l-1.3 1.3M64.3 54.6l-.4 .8M64.3 54.6l-.8 .4M64.3 55.7v.1M64.4 55.7l-1.3 1.2M70.5 41.6v4.6h6.8M77.3 46.2l2.3 2.3v22.8"/>
<path d="M102.4 55.3v16M109.3 59.9v11.4M109.3 43.9h5M109.3 50.8h5M111.6 59.9v11.4M115.7 43.9h5M115.7 50.8h5M116.2 59.9v11.4M118.4 59.9v11.4M120.7 59.9v11.4M123 59.9h-16v11.4M166.5 43.9h4.5"/>
<path d="M166.5 50.8h4.5M166.5 55.3h4.5M166.5 53h4.5M166.5 48.5h4.5M166.5 46.2h4.5M166.5 41.6h4.5M24.7 64.5v6.8M27 64.5v6.8M29.3 66.8v4.5M31.6 64.5v6.8M33.9 66.8v4.5M36.2 66.8v4.5"/>
<path d="M38.5 66.8v4.5M40.7 66.8v4.5M45.3 64.5v6.8M47.6 64.5v6.8M54.5 66.8v4.5M56.7 66.8v4.5M59 66.8v4.5M61.3 66.8v4.5M65.9 64.5v6.8M70.5 66.8v4.5M72.7 66.8v4.5M78.7 73.4v13.4"/>
<path d="M81.9 66.8v4.5M84.2 66.8v4.5M86.5 66.8v4.5M88.8 66.8v4.5M93.3 66.8v4.5M95.6 66.8v4.5M97.9 66.8v4.5M100.2 71.3v-6.8h13.7v6.8M104.7 64.5v6.8M136.7 64.5v9.1M139 64.5v9.1M141.3 64.5v4.5"/>
<path d="M143.6 64.5v4.5M145.9 64.5v4.5M148.2 64.5v4.5M150.5 64.5v4.5M152.7 64.5v4.5M155 64.5v4.5M157.3 64.5v4.5M159.6 64.5v4.5M160 73.8l.3 .3h.9l.2 .2M160.3 73.4h.9l-.5 .7zM160.3 73.4v.1M160.4 73.4v.2"/>
<path d="M160.5 73.4v.4M160.7 73.4v.6M160.9 73.4v.5M161 73.4v.3M161.1 73.4v.2M161.9 64.5v6.8M161.9 73.6l.9-.7v1.4zM161.9 73.6h1.6M161.9 73.6v13.7M162 73.5v.2M162.1 73.4v.4M162.2 73.3v.6"/>
<path d="M162.3 73.3v.7M162.5 73.2v.8M162.6 73.1v1M162.7 73v1.2M163.5 71.3h-2.8v4.6h2.8M164.2 64.5v4.5h2.3M166.5 75.9v2.3M173.3 66.8v9.1h-9.1M166.5 82.8v2.2h-4.6M24.7 135.3v4.6M27 135.3v4.6M29.3 135.3v4.6"/>
<path d="M31.6 135.3v9.2M33.9 135.3v6.9M36.2 135.3v6.9M38.5 135.3v4.6M40.7 135.3v4.6M45.3 135.3v9.2M47.6 135.3v9.2M49.9 135.3v4.6M52.2 135.3v4.6M54.5 135.3v4.6M56.7 135.3v9.2M59 135.3v9.2"/>
<path d="M61.3 135.3v9.2M65.9 135.3v4.6M68.2 135.3v4.6M70.5 135.3v9.2M72.7 135.3v9.2M75 135.3v4.6M77.3 135.3v4.6M79.6 135.3v4.6M81.9 135.3v4.6M86.5 135.3v4.6M88.8 135.3v4.6M91 135.3v4.6"/>
<path d="M93.3 135.3v4.6M95.6 135.3v4.6M97.9 135.3v4.6M100.2 135.3v4.6M102.4 135.3v6.9M107 135.3v4.6M109.3 135.3v4.6M111.6 135.3v4.6M113.9 135.3v4.6M116.2 135.3v6.9M118.4 135.3v6.9M120.7 135.3v6.9"/>
<path d="M123 135.3v4.6M145.9 128.5v2.2h2.3v9.8h-1.2M153.2 126.2h-2.7v6.8M154.6 126.2h16.4v9.1h-6.8v7.4h-.4M157.3 121.6v2.3h-9.1v-2.3h-2.3v2.3M159.6 121.6v21.4h.4M161.9 130.7h-6.9v2.3h-11.4v7.5h1.2M161.9 121.6v6.9h6.8v4.5h-6.8v7.4M164.2 121.6v4.6M166.5 130.7h2.2M134.5 158.2h4.5M143.6 158.2h2.3"/>
<path d="M144.1 145.9h-.5v10M145.1 145.8l1.7 .6v1.2M145.1 145.3v1.1l1.7 .6M145.4 142.6v.6M145.4 142.3l.6 .3-.7 .6zM145.5 142.3v.8M145.6 142.4v.6M145.7 142.5v.4M145.8 142.5v.3M145.9 148.6v14.2M145.9 142.6v.1M146 141.9l-.7 1.3"/>
<path d="M146.4 142.7v.7M146.5 142.5l.5 .4-.7 .5zM146.5 142.6v.7M146.6 142.6v.6M146.7 142.7v.4M146.9 142.8v.2M147 142.8v.1M147 142.2l-.7 1.2M147.8 146.2h.4v7.4h2.3M155 158.2v4.6h9.2v-2.3M160.8 148.5h-1.2v7.4M161.3 145.7l.7 1.3"/>
<path d="M161.3 145.7l.7 .6-.6 .3zM161.4 145.8v.7M161.5 145.9v.7M161.6 146v.5M161.7 146.1v.4M161.8 146.2v.2M161.9 146.2v.1M162.3 145.5l.7 1.2M162.3 145.5l.2 .9M162.3 145.5l.7 .6-.5 .3M162.3 145.5v.1M162.5 145.6v.8"/>
<path d="M162.6 145.7v.6M162.7 145.8v.5M162.8 145.9v.3M162.8 141.4v1.1l-1.7 .6M162.8 141.9l-1.7 .6v1.2M162.9 145.9v.3M163 146v.1M163 148.5h1.2v7.4M45.3 167.3v5.1M45.3 173.7v23.3M52.2 169.1v7.4h-18.3v6.8M54.5 169.1v9.7l2.2 2.2v2.3"/>
<path d="M56.7 169.1v9.7l-2.2 2.2v2.3M59 169.1v7.4M61.3 169.1v5.1h-2.3M95.6 176.5v5M100.2 176.5v5M111.6 171.9v9.1h2.3v9.2M113.9 171.9v6.9h4.5v11.4M116.2 171.9v2.3h2.2M141.3 176.5v9.1M179.5 179.6l.4-.4-.2 .5M180.1 178.8l-.3 1.1-.4-.3zM180.2 178.8l-1.3 2.2"/>
<path d="M180.2 178.8h4.5M33.9 190.2h-2.3v43.4h41.1v9.1M33.9 187.9v4.6M33.9 197v2.3h2.3M47.6 197v-4.5h13.7v4.5M49.9 181v5.1M49.9 187.4v9.6M54.5 187.9v9.1M56.7 187.9v9.1M60.5 199.1v6.4M72.7 192.5v4.5M75 192.5h-4.5v4.5"/>
<path d="M86.5 192.5v5M86.5 198.9v5M95.6 182.9v7.3M100.2 182.9v7.3M111.6 185.6v4.6M116.2 185.6v4.6M141.3 199.3v6.9M141.3 183.3h2.3M145.9 192.5h4.6M145.9 183.3h4.6M161.9 183.3v16h13.7l1.3 2.3M164.2 183.3v18.3h-2.3v6.9"/>
<path d="M171 190.2v4.6h6.9v-2.3M175.6 181h4.5M176.9 181l-1.3-2.2h-2.3v6.8h-6.8v-2.3M177.9 181v6.9M180.1 199.3l-.3 1.1-.4-.3zM184.7 199.3h-4.5l-1.3 2.3M45.3 215.3v13.7h2.3v13.7M47.6 215.3v11.5h13.7v15.9M51.3 209.4v3.8M52.2 215.3v2.3M53.6 209.4v3.8M54.5 215.3v2.3"/>
<path d="M55.9 209.3v3.9M56.7 215.3v2.3M58.2 209.1v4.1M59 215.3v2.3M60.5 209v4.2M61.3 215.3v2.3M62.7 211.3v1.9M63.6 215.3v2.3M65.9 215.3v2.3M68.2 215.3v2.3M70.5 215.3v2.3M72.7 215.3v2.3"/>
<path d="M86.5 201.6h4.5M93.3 213v7.3M97.9 213v11.5h-4.6v-2.8M102.4 213v11.5h4.6v-2.8M107 213v7.3M111.6 213v4.6M113.9 213v16h-54.9v13.7M116.2 213v4.6M118.4 213v18.3h-73.1v11.4M120.7 201.6h6.9M137.3 206.2h1.2M137.9 205.6v1.2"/>
<path d="M139 206.2h4.6M145.9 206.2h4.6M166.5 206.2h-2.3v2.3M171 208.5v6.8h6.9v-2.3M175.6 201.6h4.5M177.9 201.6v6.9M179.5 200.2l.4-.4-.2 .5M52.2 238.2v4.5M54.5 238.2v4.5M68.2 233.6v9.1M70.5 233.6v9.1M77.3 235.9h-11.4v6.8"/>
<path d="M137.3 222.2h1.2M137.9 221.6v1.2M139 222.2h2.3v2.3M150.5 222.2h-6.9v2.3M45.3 256.5v6.8M52.2 256.5v4.5M59 256.5v6.8M139 242.7v6.9M139 254.2v9.1M141.3 242.7v6.9M141.3 254.2v9.1M143.6 242.7v6.9"/>
<path d="M143.6 254.2v9.1M145.9 242.7v6.9M145.9 254.2v9.1M148.2 254.2v6.8M150.5 245h-2.3v4.6M170.5 255.3h1.1M171 249.6v4.6M171 254.7v1.2M173.3 249.6v9.1M175.6 249.6v9.1M177.9 249.6v2.3h2.3M65.9 267.9h-4.6v2.3"/>
<path d="M70.5 272.5h6.8M70.5 267.9h6.8"/>
<circle cx="77.3" cy="38" r=".89"/>
<circle cx="79.6" cy="38" r=".89"/>
<circle cx="81.9" cy="38" r=".89"/>
<circle cx="84.2" cy="38" r=".89"/>
<circle cx="52.2" cy="168.2" r=".89"/>
<circle cx="54.5" cy="168.2" r=".89"/>
<circle cx="56.7" cy="168.2" r=".89"/>
<circle cx="59" cy="168.2" r=".89"/>
<circle cx="61.3" cy="168.2" r=".89"/>
<circle cx="177.9" cy="179.9" r="2.75"/>
<circle cx="177.9" cy="200.5" r="2.75"/>
</g>
<g fill="none" stroke="#000" stroke-width=".23">
<path d="M49.1 39.3h1.6v4.6h-1.6zM51.4 39.3h1.6v4.6h-1.6zM56.7 35.3v3.5M59.6 37h3.4M69.3 34.2l1.2-1.7 1.1 1.7M69.7 37h1.5v4.6h-1.5zM88.8 27.9h11.4v11.4h-11.4zM111 35.9l-1.7 1.1 1.7 1.2M111 29l-1.7 1.2 1.7 1.1M120.7 28.5v3.4M120.7 35.3v3.5M134.5 30.2h32v34.3h-32z"/>
<path d="M48.7 55.3h2.3M49.9 55.3l1.1 2.3h-2.3zM51 48.5h2.3M52.2 48.5l1.1 2.3h-2.3zM60.2 55.3h2.3M60.5 41.6h1.6v4.6h-1.6zM61.3 55.3l1.2 2.3h-2.3zM80.8 44.5l1.1 1.7 1.1-1.7M86.5 42.2v3.4M89.9 46.8l1.1 1.7 1.2-1.7M101.3 57l1.1-1.7 1.2 1.7M102.4 44.5v3.4"/>
<path d="M111 49.6l-1.7 1.2 1.7 1.1M111 42.8l-1.7 1.1 1.7 1.1M120.7 42.2v3.4M120.7 49v3.5M123 58.2v3.4M22.5 71.3h102.8v64h-102.8zM163.5 70.8v1.1M163.5 72.9v1.4M163.5 75.3v1.2M164.2 71.3v4.6M165.7 78.2h1.6v4.6h-1.6zM166.5 67.3v3.5"/>
<path d="M160.7 85.6l1.2 1.7 1.1-1.7M145 139.3l2 1.2-2 1.1zM145.1 123.9h1.6v4.6h-1.6zM145.1 139.4v2.1M145.3 139.5v1.9M145.5 139.6v1.7M145.7 139.7v1.5M145.9 139.8v1.3M146.1 139.9v1.1M147 139.3v2.3M161.9 129.9h4.6v1.7h-4.6zM136.2 157l-1.7 1.2 1.7 1.1"/>
<path d="M139 157.4h4.6v1.6h-4.6zM142.5 154.2l1.1 1.7 1.1-1.7M146.3 140v.9M146.5 140.2v.6M146.7 140.3v.4M146.9 140.4v.2M150.5 151.9v3.4M158.5 154.2l1.1 1.7 1.1-1.7M161 147.3l2 1.2-2 1.1zM161 147.4v2.2M161.2 147.5v2M161.4 147.6v1.8"/>
<path d="M161.6 147.7v1.5M161.8 147.8v1.3M162 147.9v1.1M162.2 148v.9M162.4 148.1v.7M162.6 148.2v.5M162.8 148.3v.3M163 147.3v2.3M163.4 155.9h1.6v4.6h-1.6zM43.6 167.3h3.4M57.3 176.5h3.4M93.9 176.5h3.4"/>
<path d="M98.4 176.5h3.5M118.4 172.5v3.4M140.2 178.2l1.1-1.7 1.2 1.7M184.7 177v3.5M33.1 183.3h1.6v4.6h-1.6zM33.1 192.5h1.6v4.5h-1.6zM36.2 197.6v3.4M43 197h32v18.3h-32zM48.2 181h3.4M53.7 183.3h1.6v4.6h-1.6zM55.9 183.3h1.7v4.6h-1.7zM75 190.8v3.4"/>
<path d="M84.8 192.5h3.4M127.6 199.9v3.4M139 185.6h6.9v13.7h-6.9zM143.6 181.9h.8v2.8h-.8zM150.5 181.6v3.4M150.5 190.8v3.4M177.1 187.9h1.6v4.6h-1.6zM184.7 197.6v3.4M85.3 202.2l1.2 1.7 1.1-1.7M143.6 204.8h.8v2.8h-.8zM150.5 204.5v3.4M166.5 204.5v3.4"/>
<path d="M177.1 208.5h1.6v4.5h-1.6zM77.3 234.2v3.4M150.5 220.5v3.4M147 259.3l1.2 1.7 1.1-1.7M150.5 243.3v3.4M180.2 250.2v3.4M60.2 268.5l1.1 1.7 1.2-1.7M77.3 266.2v3.4M77.3 270.7v3.5"/>
<circle cx="137.9" cy="206.2" r="1.14"/>
<circle cx="137.9" cy="222.2" r="1.14"/>
<circle cx="171" cy="255.3" r="1.14"/>
</g>
<path d="M75 35.9h11.5v6.9h-11.5zM141.3 137.6h9.2v13.7h-9.2zM157.3 137.6h9.2v13.7h-9.2zM144.1 144.5h3.6v2a1.82 1.82 0 0 1-1.8 1.9 1.82 1.82 0 0 1-1.8-1.9zM160.5 141.1a1.83 1.83 0 0 1 2.1-.5 1.83 1.83 0 0 1 1.1 1.8v2.1h-3.7l.1-2.5zM49.9 166.2h13.7v6.8h-13.7zM91 190.2h29.7v22.8h-29.7zM43 242.7h32v13.8h-32zM136.7 248.5h13.8v6.8h-13.8z" fill="none" stroke="#000" stroke-width=".38"/>
<g fill="#000" stroke="#000" stroke-width=".19">
<path d="M114.3 35.2h.5v3.7h-.5zM114.3 28.4h.5v3.6h-.5zM115.3 35.2h.4v3.7h-.4zM115.3 28.4h.4v3.6h-.4zM114.3 48.9h.5v3.7h-.5zM114.3 42.1h.5v3.6h-.5zM115.3 48.9h.4v3.7h-.4zM115.3 42.1h.4v3.6h-.4zM153.2 124.4h.4v3.6h-.4zM154.1 124.4h.5v3.6h-.5zM43.5 172.3h3.6v.5h-3.6zM43.5 173.3h3.6v.4h-3.6z"/>
<path d="M48.1 186.1h3.6v.4h-3.6zM48.1 187h3.6v.4h-3.6zM84.6 197.5h3.7v.5h-3.7zM84.6 198.4h3.7v.5h-3.7zM93.8 181.5h3.6v.4h-3.6zM93.8 182.4h3.6v.5h-3.6zM98.3 181.5h3.7v.4h-3.7zM98.3 182.4h3.7v.5h-3.7zM145.1 181.8h.8v3h-.8zM145.1 204.7h.8v3h-.8zM91.5 220.3h3.6v.5h-3.6zM91.5 221.3h3.6v.4h-3.6z"/>
<path d="M105.2 220.3h3.6v.5h-3.6zM105.2 221.3h3.6v.4h-3.6z"/>
</g>
<g fill="none" stroke="#000" stroke-width=".55">
<path d="M157.3 120.5v1.1M159.6 120.5v1.1M161.9 120.5v1.1M164.2 120.5v1.1M111.6 170.8v1.1M113.9 170.8v1.1M116.2 170.8v1.1M161.9 182.2v1.1M164.2 182.2v1.1M166.5 182.2v1.1M161.9 208.5v1.1M164.2 208.5v1.1"/>
<path d="M141.3 224.5v1.1M143.6 224.5v1.1M139 249.6v1.1M139 253v1.2M141.3 249.6v1.1M141.3 253v1.2M143.6 249.6v1.1M143.6 253v1.2M145.9 249.6v1.1M145.9 253v1.2M148.2 249.6v1.1M148.2 253v1.2"/>
<path d="M171 248.5v1.1M173.3 248.5v1.1M175.6 248.5v1.1M177.9 248.5v1.1"/>
</g>
<g fill="#000" stroke="#000" stroke-width=".19">
<circle cx="52.2" cy="37.1" r=".47"/>
<circle cx="77.3" cy="46.2" r=".47"/>
<circle cx="91" cy="43.9" r=".47"/>
<circle cx="109.3" cy="59.9" r=".47"/>
<circle cx="111.6" cy="59.9" r=".47"/>
<circle cx="116.2" cy="59.9" r=".47"/>
<circle cx="118.4" cy="59.9" r=".47"/>
<circle cx="120.7" cy="59.9" r=".47"/>
<circle cx="102.4" cy="64.5" r=".47"/>
<circle cx="104.7" cy="64.5" r=".47"/>
<circle cx="161.9" cy="75.9" r=".32"/>
<circle cx="161.9" cy="71.4" r=".32"/>
<circle cx="166.5" cy="75.9" r=".47"/>
<circle cx="161.9" cy="85.1" r=".47"/>
<circle cx="150.5" cy="133.1" r=".47"/>
<circle cx="159.6" cy="130.8" r=".47"/>
<circle cx="164.2" cy="126.2" r=".47"/>
<circle cx="168.7" cy="130.8" r=".47"/>
<circle cx="145.9" cy="158.2" r=".47"/>
<circle cx="45.3" cy="176.5" r=".47"/>
<circle cx="59" cy="174.2" r=".47"/>
<circle cx="33.9" cy="190.2" r=".47"/>
<circle cx="49.9" cy="192.5" r=".47"/>
<circle cx="72.7" cy="192.5" r=".47"/>
<circle cx="141.3" cy="183.3" r=".47"/>
<circle cx="86.5" cy="201.6" r=".47"/>
<circle cx="141.3" cy="206.2" r=".47"/>
<circle cx="68.2" cy="233.6" r=".47"/>
<circle cx="70.5" cy="233.6" r=".47"/>
</g>
<use href="#words"/>
</svg>
